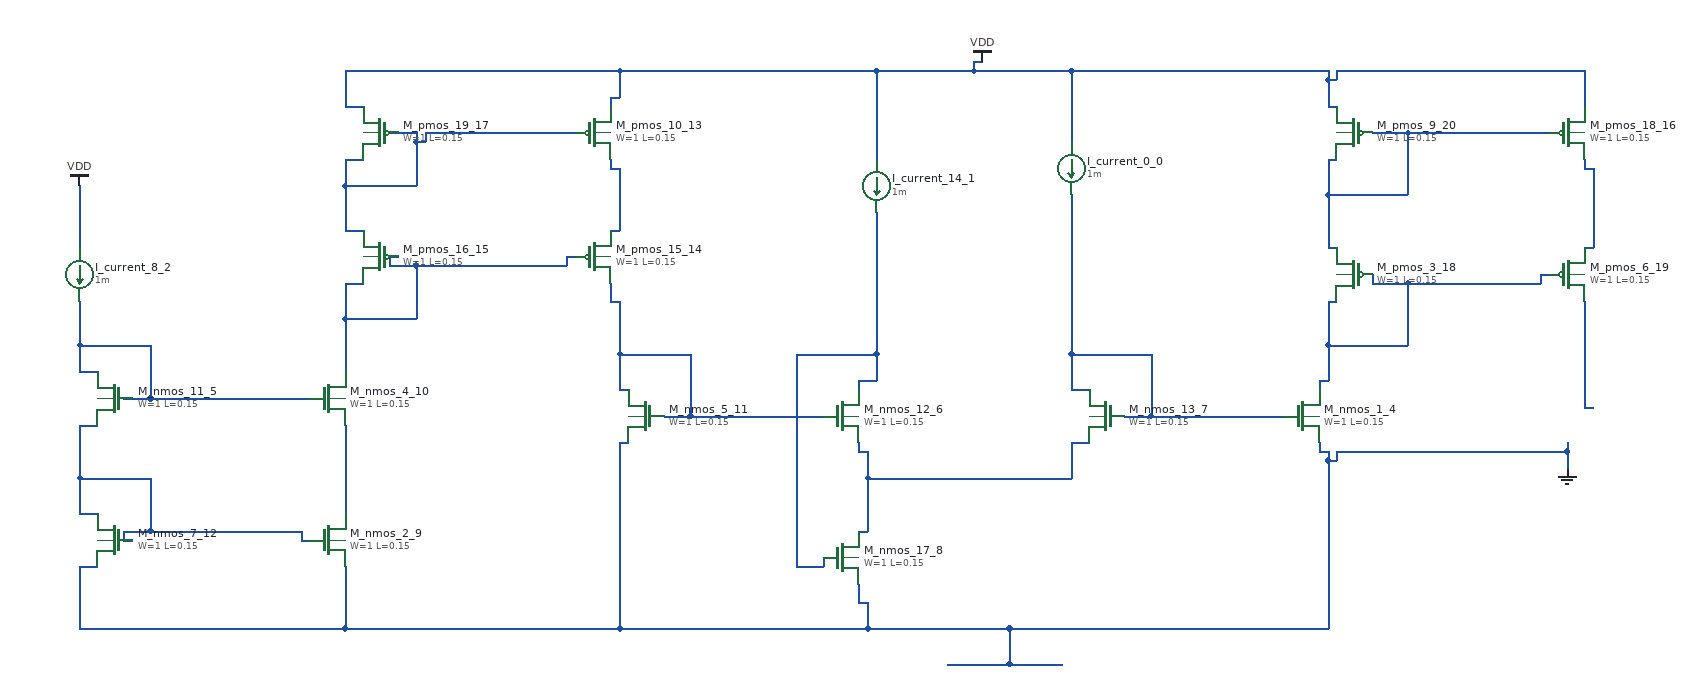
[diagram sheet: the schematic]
v {xschem version=3.4.8 file_version=1.2}
G {}
K {}
V {}
S {}
E {}
C {devices/isource.sym} 1280 260 0 0 {name="I_current_0_0" value=1m}
C {devices/isource.sym} 1060 280 0 0 {name="I_current_14_1" value=1m}
C {devices/isource.sym} 160 380 0 0 {name="I_current_8_2" value=1m}
C {devices/gnd.sym} 1840 600 0 0 {name="l_gnd_21_3" lab="GND"}
C {sky130_fd_pr/nfet3_01v8.sym} 1540 540 0 0 {name="M_nmos_1_4"
W=1
L=0.15
body=GND
nf=1
mult=1
ad="expr('int((@nf + 1)/2) * @W / @nf * 0.29')"
pd="expr('2*int((@nf + 1)/2) * (@W / @nf + 0.29)')"
as="expr('int((@nf + 2)/2) * @W / @nf * 0.29')"
ps="expr('2*int((@nf + 2)/2) * (@W / @nf + 0.29)')"
nrd="expr('0.29 / @W ')" nrs="expr('0.29 / @W ')"
sa=0 sb=0 sd=0
model=nfet_01v8
spiceprefix=X
}
C {sky130_fd_pr/nfet3_01v8.sym} 200 520 0 1 {name="M_nmos_11_5"
W=1
L=0.15
body=GND
nf=1
mult=1
ad="expr('int((@nf + 1)/2) * @W / @nf * 0.29')"
pd="expr('2*int((@nf + 1)/2) * (@W / @nf + 0.29)')"
as="expr('int((@nf + 2)/2) * @W / @nf * 0.29')"
ps="expr('2*int((@nf + 2)/2) * (@W / @nf + 0.29)')"
nrd="expr('0.29 / @W ')" nrs="expr('0.29 / @W ')"
sa=0 sb=0 sd=0
model=nfet_01v8
spiceprefix=X
}
C {sky130_fd_pr/nfet3_01v8.sym} 1020 540 0 0 {name="M_nmos_12_6"
W=1
L=0.15
body=GND
nf=1
mult=1
ad="expr('int((@nf + 1)/2) * @W / @nf * 0.29')"
pd="expr('2*int((@nf + 1)/2) * (@W / @nf + 0.29)')"
as="expr('int((@nf + 2)/2) * @W / @nf * 0.29')"
ps="expr('2*int((@nf + 2)/2) * (@W / @nf + 0.29)')"
nrd="expr('0.29 / @W ')" nrs="expr('0.29 / @W ')"
sa=0 sb=0 sd=0
model=nfet_01v8
spiceprefix=X
}
C {sky130_fd_pr/nfet3_01v8.sym} 1320 540 0 1 {name="M_nmos_13_7"
W=1
L=0.15
body=GND
nf=1
mult=1
ad="expr('int((@nf + 1)/2) * @W / @nf * 0.29')"
pd="expr('2*int((@nf + 1)/2) * (@W / @nf + 0.29)')"
as="expr('int((@nf + 2)/2) * @W / @nf * 0.29')"
ps="expr('2*int((@nf + 2)/2) * (@W / @nf + 0.29)')"
nrd="expr('0.29 / @W ')" nrs="expr('0.29 / @W ')"
sa=0 sb=0 sd=0
model=nfet_01v8
spiceprefix=X
}
C {sky130_fd_pr/nfet3_01v8.sym} 1020 700 0 0 {name="M_nmos_17_8"
W=1
L=0.15
body=GND
nf=1
mult=1
ad="expr('int((@nf + 1)/2) * @W / @nf * 0.29')"
pd="expr('2*int((@nf + 1)/2) * (@W / @nf + 0.29)')"
as="expr('int((@nf + 2)/2) * @W / @nf * 0.29')"
ps="expr('2*int((@nf + 2)/2) * (@W / @nf + 0.29)')"
nrd="expr('0.29 / @W ')" nrs="expr('0.29 / @W ')"
sa=0 sb=0 sd=0
model=nfet_01v8
spiceprefix=X
}
C {sky130_fd_pr/nfet3_01v8.sym} 440 680 0 0 {name="M_nmos_2_9"
W=1
L=0.15
body=GND
nf=1
mult=1
ad="expr('int((@nf + 1)/2) * @W / @nf * 0.29')"
pd="expr('2*int((@nf + 1)/2) * (@W / @nf + 0.29)')"
as="expr('int((@nf + 2)/2) * @W / @nf * 0.29')"
ps="expr('2*int((@nf + 2)/2) * (@W / @nf + 0.29)')"
nrd="expr('0.29 / @W ')" nrs="expr('0.29 / @W ')"
sa=0 sb=0 sd=0
model=nfet_01v8
spiceprefix=X
}
C {sky130_fd_pr/nfet3_01v8.sym} 440 520 0 0 {name="M_nmos_4_10"
W=1
L=0.15
body=GND
nf=1
mult=1
ad="expr('int((@nf + 1)/2) * @W / @nf * 0.29')"
pd="expr('2*int((@nf + 1)/2) * (@W / @nf + 0.29)')"
as="expr('int((@nf + 2)/2) * @W / @nf * 0.29')"
ps="expr('2*int((@nf + 2)/2) * (@W / @nf + 0.29)')"
nrd="expr('0.29 / @W ')" nrs="expr('0.29 / @W ')"
sa=0 sb=0 sd=0
model=nfet_01v8
spiceprefix=X
}
C {sky130_fd_pr/nfet3_01v8.sym} 800 540 0 1 {name="M_nmos_5_11"
W=1
L=0.15
body=GND
nf=1
mult=1
ad="expr('int((@nf + 1)/2) * @W / @nf * 0.29')"
pd="expr('2*int((@nf + 1)/2) * (@W / @nf + 0.29)')"
as="expr('int((@nf + 2)/2) * @W / @nf * 0.29')"
ps="expr('2*int((@nf + 2)/2) * (@W / @nf + 0.29)')"
nrd="expr('0.29 / @W ')" nrs="expr('0.29 / @W ')"
sa=0 sb=0 sd=0
model=nfet_01v8
spiceprefix=X
}
C {sky130_fd_pr/nfet3_01v8.sym} 200 680 0 1 {name="M_nmos_7_12"
W=1
L=0.15
body=GND
nf=1
mult=1
ad="expr('int((@nf + 1)/2) * @W / @nf * 0.29')"
pd="expr('2*int((@nf + 1)/2) * (@W / @nf + 0.29)')"
as="expr('int((@nf + 2)/2) * @W / @nf * 0.29')"
ps="expr('2*int((@nf + 2)/2) * (@W / @nf + 0.29)')"
nrd="expr('0.29 / @W ')" nrs="expr('0.29 / @W ')"
sa=0 sb=0 sd=0
model=nfet_01v8
spiceprefix=X
}
C {sky130_fd_pr/pfet3_01v8.sym} 740 220 0 0 {name="M_pmos_10_13"
W=1
L=0.15
body=VDD
nf=1
mult=1
ad="expr('int((@nf + 1)/2) * @W / @nf * 0.29')"
pd="expr('2*int((@nf + 1)/2) * (@W / @nf + 0.29)')"
as="expr('int((@nf + 2)/2) * @W / @nf * 0.29')"
ps="expr('2*int((@nf + 2)/2) * (@W / @nf + 0.29)')"
nrd="expr('0.29 / @W ')" nrs="expr('0.29 / @W ')"
sa=0 sb=0 sd=0
model=pfet_01v8
spiceprefix=X
}
C {sky130_fd_pr/pfet3_01v8.sym} 740 360 0 0 {name="M_pmos_15_14"
W=1
L=0.15
body=VDD
nf=1
mult=1
ad="expr('int((@nf + 1)/2) * @W / @nf * 0.29')"
pd="expr('2*int((@nf + 1)/2) * (@W / @nf + 0.29)')"
as="expr('int((@nf + 2)/2) * @W / @nf * 0.29')"
ps="expr('2*int((@nf + 2)/2) * (@W / @nf + 0.29)')"
nrd="expr('0.29 / @W ')" nrs="expr('0.29 / @W ')"
sa=0 sb=0 sd=0
model=pfet_01v8
spiceprefix=X
}
C {sky130_fd_pr/pfet3_01v8.sym} 500 360 0 1 {name="M_pmos_16_15"
W=1
L=0.15
body=VDD
nf=1
mult=1
ad="expr('int((@nf + 1)/2) * @W / @nf * 0.29')"
pd="expr('2*int((@nf + 1)/2) * (@W / @nf + 0.29)')"
as="expr('int((@nf + 2)/2) * @W / @nf * 0.29')"
ps="expr('2*int((@nf + 2)/2) * (@W / @nf + 0.29)')"
nrd="expr('0.29 / @W ')" nrs="expr('0.29 / @W ')"
sa=0 sb=0 sd=0
model=pfet_01v8
spiceprefix=X
}
C {sky130_fd_pr/pfet3_01v8.sym} 1840 220 0 0 {name="M_pmos_18_16"
W=1
L=0.15
body=VDD
nf=1
mult=1
ad="expr('int((@nf + 1)/2) * @W / @nf * 0.29')"
pd="expr('2*int((@nf + 1)/2) * (@W / @nf + 0.29)')"
as="expr('int((@nf + 2)/2) * @W / @nf * 0.29')"
ps="expr('2*int((@nf + 2)/2) * (@W / @nf + 0.29)')"
nrd="expr('0.29 / @W ')" nrs="expr('0.29 / @W ')"
sa=0 sb=0 sd=0
model=pfet_01v8
spiceprefix=X
}
C {sky130_fd_pr/pfet3_01v8.sym} 500 220 0 1 {name="M_pmos_19_17"
W=1
L=0.15
body=VDD
nf=1
mult=1
ad="expr('int((@nf + 1)/2) * @W / @nf * 0.29')"
pd="expr('2*int((@nf + 1)/2) * (@W / @nf + 0.29)')"
as="expr('int((@nf + 2)/2) * @W / @nf * 0.29')"
ps="expr('2*int((@nf + 2)/2) * (@W / @nf + 0.29)')"
nrd="expr('0.29 / @W ')" nrs="expr('0.29 / @W ')"
sa=0 sb=0 sd=0
model=pfet_01v8
spiceprefix=X
}
C {sky130_fd_pr/pfet3_01v8.sym} 1600 380 0 1 {name="M_pmos_3_18"
W=1
L=0.15
body=VDD
nf=1
mult=1
ad="expr('int((@nf + 1)/2) * @W / @nf * 0.29')"
pd="expr('2*int((@nf + 1)/2) * (@W / @nf + 0.29)')"
as="expr('int((@nf + 2)/2) * @W / @nf * 0.29')"
ps="expr('2*int((@nf + 2)/2) * (@W / @nf + 0.29)')"
nrd="expr('0.29 / @W ')" nrs="expr('0.29 / @W ')"
sa=0 sb=0 sd=0
model=pfet_01v8
spiceprefix=X
}
C {sky130_fd_pr/pfet3_01v8.sym} 1840 380 0 0 {name="M_pmos_6_19"
W=1
L=0.15
body=VDD
nf=1
mult=1
ad="expr('int((@nf + 1)/2) * @W / @nf * 0.29')"
pd="expr('2*int((@nf + 1)/2) * (@W / @nf + 0.29)')"
as="expr('int((@nf + 2)/2) * @W / @nf * 0.29')"
ps="expr('2*int((@nf + 2)/2) * (@W / @nf + 0.29)')"
nrd="expr('0.29 / @W ')" nrs="expr('0.29 / @W ')"
sa=0 sb=0 sd=0
model=pfet_01v8
spiceprefix=X
}
C {sky130_fd_pr/pfet3_01v8.sym} 1600 220 0 1 {name="M_pmos_9_20"
W=1
L=0.15
body=VDD
nf=1
mult=1
ad="expr('int((@nf + 1)/2) * @W / @nf * 0.29')"
pd="expr('2*int((@nf + 1)/2) * (@W / @nf + 0.29)')"
as="expr('int((@nf + 2)/2) * @W / @nf * 0.29')"
ps="expr('2*int((@nf + 2)/2) * (@W / @nf + 0.29)')"
nrd="expr('0.29 / @W ')" nrs="expr('0.29 / @W ')"
sa=0 sb=0 sd=0
model=pfet_01v8
spiceprefix=X
}
C {devices/vdd.sym} 1180 140 0 0 {name="l_vdd_22_21" lab="VDD"}
C {devices/vdd.sym} 160 280 0 0 {name="l_vdd_23_22" lab="VDD"}
N 460 190 480 190 {}
N 1570 190 1580 190 {}
N 760 180 770 180 {}
N 1570 160 1580 160 {}
N 460 150 770 150 {}
N 770 150 1060 150 {}
N 1060 150 1170 150 {}
N 1170 150 1280 150 {}
N 1280 150 1570 150 {}
N 1580 150 1860 150 {}
N 1170 140 1180 140 {}
N 160 350 160 280 {}
N 460 190 460 150 {}
N 760 190 760 180 {}
N 770 180 770 150 {}
N 1060 250 1060 150 {}
N 1170 150 1170 140 {}
N 1280 230 1280 150 {}
N 1570 190 1570 160 {}
N 1570 160 1570 150 {}
N 1580 160 1580 150 {}
N 1860 190 1860 150 {}
N 1340 540 1370 540 {}
N 1370 540 1520 540 {}
N 1280 510 1300 510 {}
N 1280 470 1370 470 {}
N 1280 510 1280 470 {}
N 1280 470 1280 290 {}
N 1370 540 1370 470 {}
N 760 330 770 330 {}
N 760 260 770 260 {}
N 760 260 760 250 {}
N 770 330 770 260 {}
N 460 330 480 330 {}
N 460 280 540 280 {}
N 460 250 480 250 {}
N 540 230 550 230 {}
N 510 220 520 220 {}
N 520 220 540 220 {}
N 550 220 720 220 {}
N 460 330 460 280 {}
N 460 280 460 250 {}
N 540 280 540 230 {}
N 540 230 540 220 {}
N 550 230 550 220 {}
N 1860 350 1870 350 {}
N 1860 260 1870 260 {}
N 1860 260 1860 250 {}
N 1870 350 1870 260 {}
N 1570 350 1580 350 {}
N 1570 290 1660 290 {}
N 1570 250 1580 250 {}
N 1620 220 1660 220 {}
N 1660 220 1820 220 {}
N 1570 350 1570 290 {}
N 1570 290 1570 250 {}
N 1660 290 1660 220 {}
N 1560 500 1570 500 {}
N 1570 460 1660 460 {}
N 1570 410 1580 410 {}
N 1620 390 1660 390 {}
N 1660 390 1810 390 {}
N 1810 380 1820 380 {}
N 1560 510 1560 500 {}
N 1570 500 1570 460 {}
N 1570 460 1570 410 {}
N 1620 390 1620 380 {}
N 1660 460 1660 390 {}
N 1810 390 1810 380 {}
N 1860 530 1870 530 {}
N 1860 530 1860 410 {}
N 210 680 220 680 {}
N 410 680 420 680 {}
N 210 670 240 670 {}
N 240 670 410 670 {}
N 160 650 180 650 {}
N 160 610 240 610 {}
N 160 550 180 550 {}
N 160 650 160 610 {}
N 160 610 160 550 {}
N 210 680 210 670 {}
N 240 670 240 610 {}
N 410 680 410 670 {}
N 210 520 220 520 {}
N 220 520 240 520 {}
N 240 520 420 520 {}
N 160 490 180 490 {}
N 160 460 240 460 {}
N 160 490 160 460 {}
N 160 460 160 410 {}
N 240 520 240 460 {}
N 970 710 1000 710 {}
N 1040 500 1060 500 {}
N 970 470 1060 470 {}
N 970 710 970 470 {}
N 1000 710 1000 700 {}
N 1040 510 1040 500 {}
N 1060 500 1060 470 {}
N 1060 470 1060 310 {}
N 1040 670 1050 670 {}
N 1050 610 1280 610 {}
N 1040 580 1050 580 {}
N 1280 570 1300 570 {}
N 1040 580 1040 570 {}
N 1050 670 1050 610 {}
N 1050 610 1050 580 {}
N 1280 610 1280 570 {}
N 820 540 850 540 {}
N 850 540 1000 540 {}
N 770 510 780 510 {}
N 770 470 850 470 {}
N 760 410 770 410 {}
N 760 410 760 390 {}
N 770 510 770 470 {}
N 770 470 770 410 {}
N 850 540 850 470 {}
N 1140 820 1210 820 {}
N 1210 820 1270 820 {}
N 160 780 460 780 {}
N 460 780 770 780 {}
N 770 780 1050 780 {}
N 1050 780 1210 780 {}
N 1210 780 1570 780 {}
N 1040 750 1050 750 {}
N 160 710 180 710 {}
N 1570 590 1580 590 {}
N 1560 580 1570 580 {}
N 1580 580 1840 580 {}
N 770 570 780 570 {}
N 160 780 160 710 {}
N 460 780 460 710 {}
N 770 780 770 570 {}
N 1040 750 1040 730 {}
N 1050 780 1050 750 {}
N 1210 820 1210 780 {}
N 1560 580 1560 570 {}
N 1570 780 1570 590 {}
N 1570 590 1570 580 {}
N 1580 590 1580 580 {}
N 1840 600 1840 580 {}
N 1840 580 1840 570 {}
N 460 650 460 550 {}
N 460 430 540 430 {}
N 460 390 480 390 {}
N 510 370 540 370 {}
N 540 370 710 370 {}
N 510 360 520 360 {}
N 710 360 720 360 {}
N 460 490 460 430 {}
N 460 430 460 390 {}
N 510 370 510 360 {}
N 540 430 540 370 {}
N 710 370 710 360 {}
